VERSION 5.7 ;
  NOWIREEXTENSIONATPIN ON ;
  DIVIDERCHAR "/" ;
  BUSBITCHARS "[]" ;
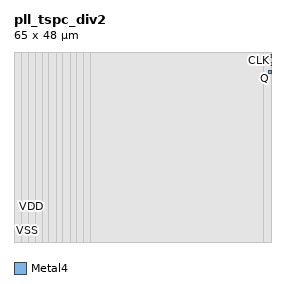
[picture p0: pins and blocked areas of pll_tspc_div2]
MACRO pll_tspc_div2
  CLASS BLOCK ;
  FOREIGN pll_tspc_div2 0.000 0.000 ;
  ORIGIN 0.000 0.000 ;
  SIZE 65.000 BY 48.000 ;
  SYMMETRY X Y ;
  PIN VSS
    DIRECTION INOUT ;
    USE GROUND ;
    PORT
      LAYER Metal4 ;
        RECT 0.690 2.690 1.310 3.310 ;
    END
  END VSS
  PIN VDD
    DIRECTION INOUT ;
    USE POWER ;
    PORT
      LAYER Metal4 ;
        RECT 4.190 8.690 4.810 9.310 ;
    END
  END VDD
  PIN RESET_B
    DIRECTION INPUT ;
    USE SIGNAL ;
    ANTENNAGATEAREA 0.312000 ;
    ANTENNADIFFAREA 2.015400 ;
    PORT
      LAYER Metal4 ;
        RECT 64.380 44.690 65.000 45.310 ;
    END
  END RESET_B
  PIN CLK
    DIRECTION INPUT ;
    USE SIGNAL ;
    ANTENNAGATEAREA 0.780000 ;
    ANTENNADIFFAREA 2.015400 ;
    PORT
      LAYER Metal4 ;
        RECT 64.380 46.690 65.000 47.310 ;
    END
  END CLK
  PIN Q
    DIRECTION OUTPUT ;
    USE SIGNAL ;
    ANTENNAGATEAREA 0.156000 ;
    ANTENNADIFFAREA 2.015400 ;
    PORT
      LAYER Metal4 ;
        RECT 64.380 42.690 65.000 43.310 ;
    END
  END Q
  OBS
    LAYER Metal1 ;
      RECT 0.000 0.000 65.000 48.000 ;
    LAYER Metal2 ;
      RECT 0.000 0.000 63.000 48.000 ;
    LAYER Metal3 ;
      RECT 0.000 0.000 63.000 48.000 ;
    LAYER Metal4 ;
      RECT 0.000 0.000 63.000 48.000 ;
    LAYER TopMetal1 ;
      RECT 0.180 0.000 1.820 48.000 ;
      RECT 3.680 0.000 5.320 48.000 ;
      RECT 7.180 0.000 8.820 48.000 ;
      RECT 10.680 0.000 12.320 48.000 ;
      RECT 14.180 0.000 15.820 48.000 ;
      RECT 17.680 0.000 19.320 48.000 ;
  END
END pll_tspc_div2
END LIBRARY
